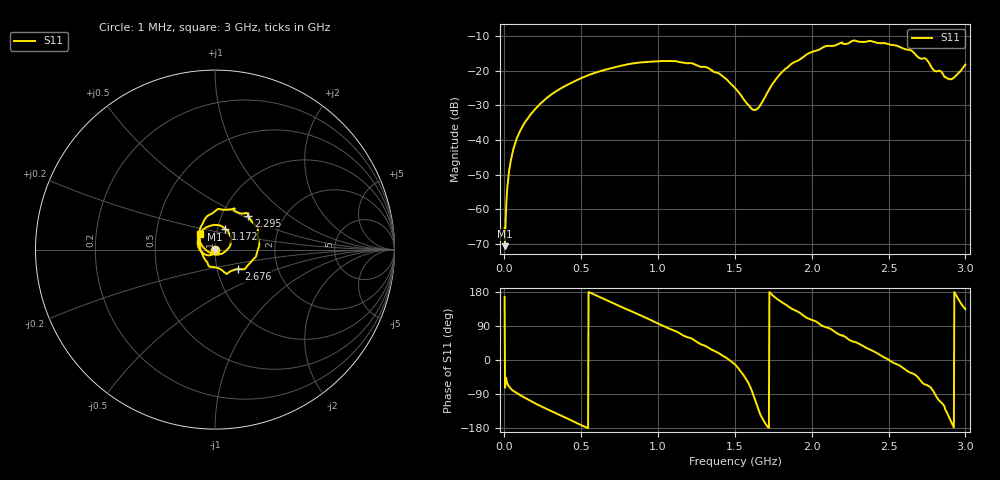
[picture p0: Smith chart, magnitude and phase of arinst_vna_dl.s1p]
!Start (Hz):  1000000.000000
!Stop (Hz):  3000000000.000000
!Points:  1000
!Bandwidth (Hz):  1000
!Data:
# Hz S RI R 50
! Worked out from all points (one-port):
!   1000 points, 1 MHz to 3 GHz, reference 50 ohm
!   lowest |S11| = -70.7 dB at 4.002 MHz (marker M1), VSWR 1.00, Z = 50 - j0.0281 ohm
!   |S11| at or under -10 dB: start of sweep to end of sweep
!   S11 on the Smith chart (normalised r, x): 1 MHz: 1.00, +0.00; 1.172 GHz: 1.09, +0.26; 2.295 GHz: 1.33, +0.54; 2.676 GHz: 1.26, -0.28; 3 GHz: 0.83, +0.15
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1000000  -0.000522 0.000129
4002002  8.4e-05 -0.000281
2.801802e7  0.00114 -0.00299
4.002603e7  0.00128 -0.00471
6.404204e7  0.000941 -0.00817
9.106006e7  6.4e-05 -0.0119
2.051361e8  -0.0122 -0.0258
3.762502e8  -0.0483 -0.0301
7.515005e8  -0.0913 0.0719
1.126751e9  0.0376 0.1295
1.171781e9  0.0584 0.1153
1.324883e9  0.0915 0.0599
1.414943e9  0.0825 0.0186
1.502001e9  0.0543 -0.0119
1.604069e9  0.00738 -0.028
1.637091e9  -0.0103 -0.0252
1.778185e9  -0.0757 0.0276
1.877251e9  -0.0894 0.0927
2.087391e9  0.0111 0.2228
2.252502e9  0.1625 0.2014
2.29453e9  0.1853 0.189
2.47465e9  0.2471 0.027
2.627752e9  0.1723 -0.1017
2.675784e9  0.1296 -0.1085
2.74483e9  0.0607 -0.1334
2.795864e9  0.0077 -0.0997
2.89493e9  -0.0662 -0.0358
3e9  -0.085 0.0874
